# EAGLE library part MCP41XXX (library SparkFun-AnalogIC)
SPI controlled single digital potentiometer by Microchip PID: COM-10613

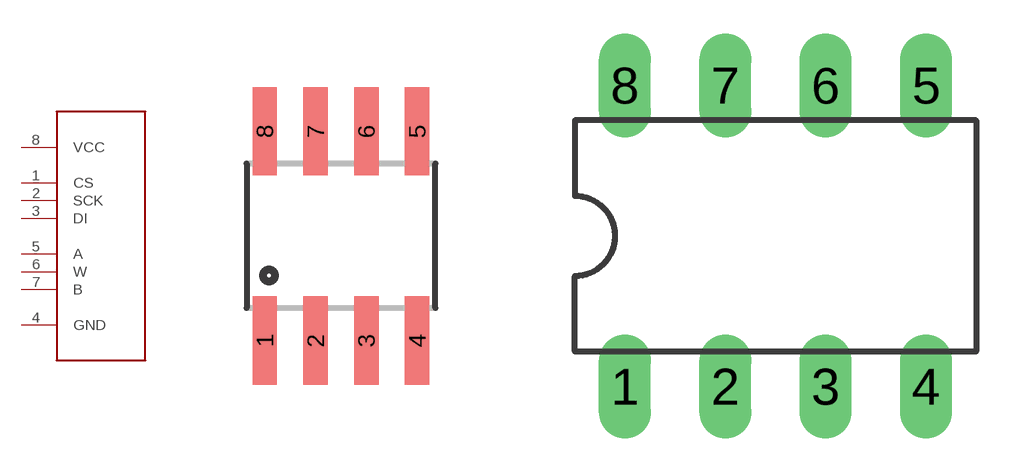
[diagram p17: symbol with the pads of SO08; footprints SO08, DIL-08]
Designator prefix U

## MCP41XXX  [SO08]
1  CS
2  SCK
3  DI
4  GND
5  A
6  W
7  B
8  VCC

## MCP41XXXDIL  [DIL-08]
Pads as for SO08

## Footprint SO08 (pad centres in mm)
Small Outline Package Fits JEDEC packages (narrow SOIC-8)
smd 0.61 x 2.21: 1 -1.905,-2.616; 2 -0.635,-2.616; 3 0.635,-2.616; 4 1.905,-2.616; 5 1.905,2.616; 6 0.635,2.616; 7 -0.635,2.616; 8 -1.905,2.616

## Footprint DIL-08 (pad centres in mm)
Dual In Line Package
drill 0.813 long: 1 -3.81,-3.81; 2 -1.27,-3.81; 3 1.27,-3.81; 4 3.81,-3.81; 5 3.81,3.81; 6 1.27,3.81; 7 -1.27,3.81; 8 -3.81,3.81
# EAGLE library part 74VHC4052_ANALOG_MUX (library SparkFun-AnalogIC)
Dual 4:1 analog mux

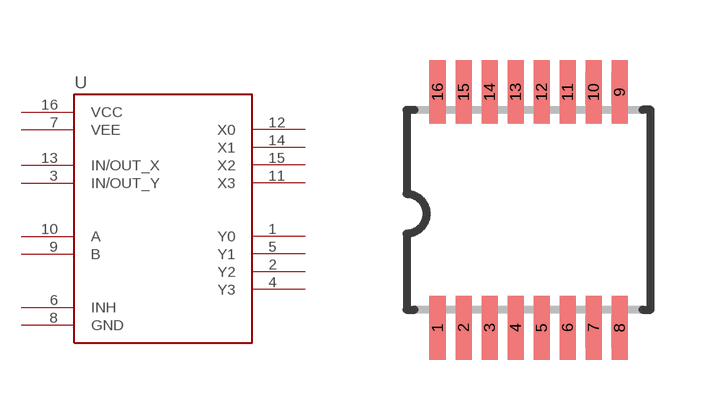
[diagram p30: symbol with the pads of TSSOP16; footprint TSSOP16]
Designator prefix U

## 74VHC4052_ANALOG_MUX  [TSSOP16]
1  Y0
2  Y2
3  IN/OUT_Y
4  Y3
5  Y1
6  INH
7  VEE
8  GND
9  B
10  A
11  X3
12  X0
13  IN/OUT_X
14  X1
15  X2
16  VCC

## Footprint TSSOP16 (pad centres in mm)
TSOP16 thin small outline package
smd 0.4 x 1.6: 1 -2.225,-2.85; 2 -1.575,-2.85; 3 -0.925,-2.85; 4 -0.275,-2.85; 5 0.375,-2.85; 6 1.025,-2.85; 7 1.675,-2.85; 8 2.325,-2.85; 9 2.325,3.05; 10 1.675,3.05; 11 1.025,3.05; 12 0.375,3.05; 13 -0.275,3.05; 14 -0.925,3.05; 15 -1.575,3.05; 16 -2.225,3.05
